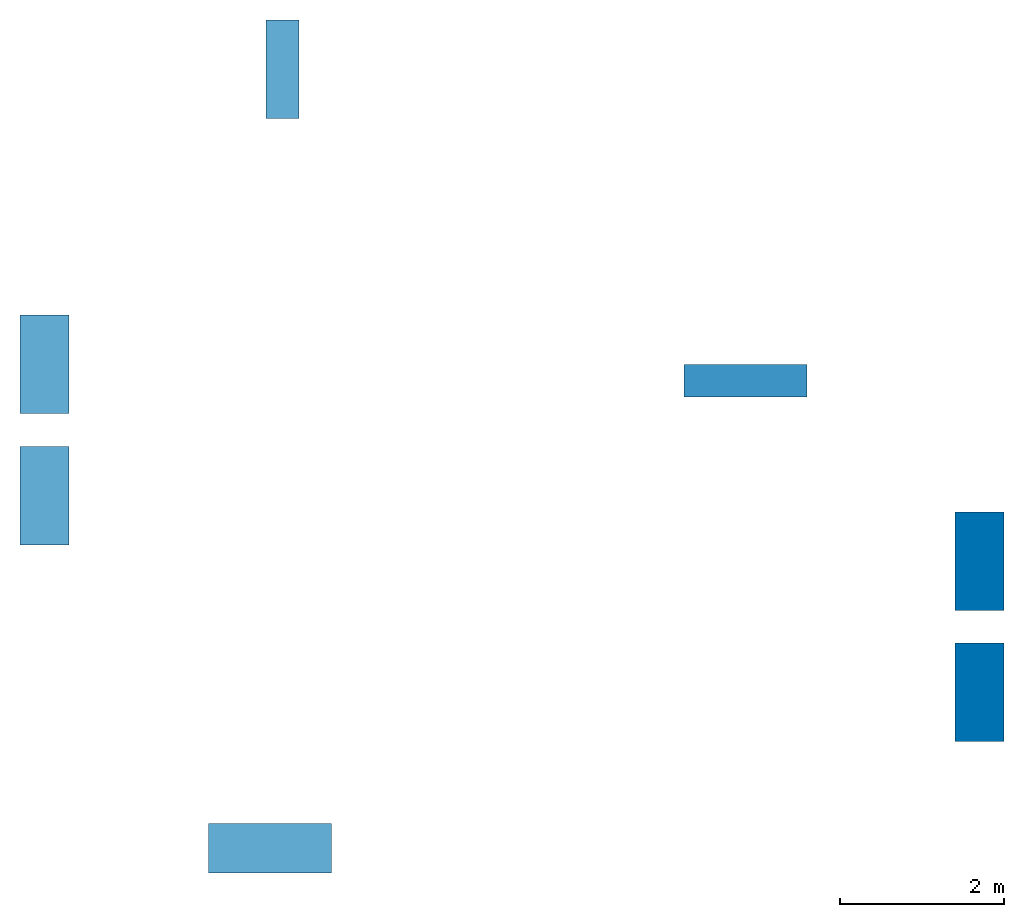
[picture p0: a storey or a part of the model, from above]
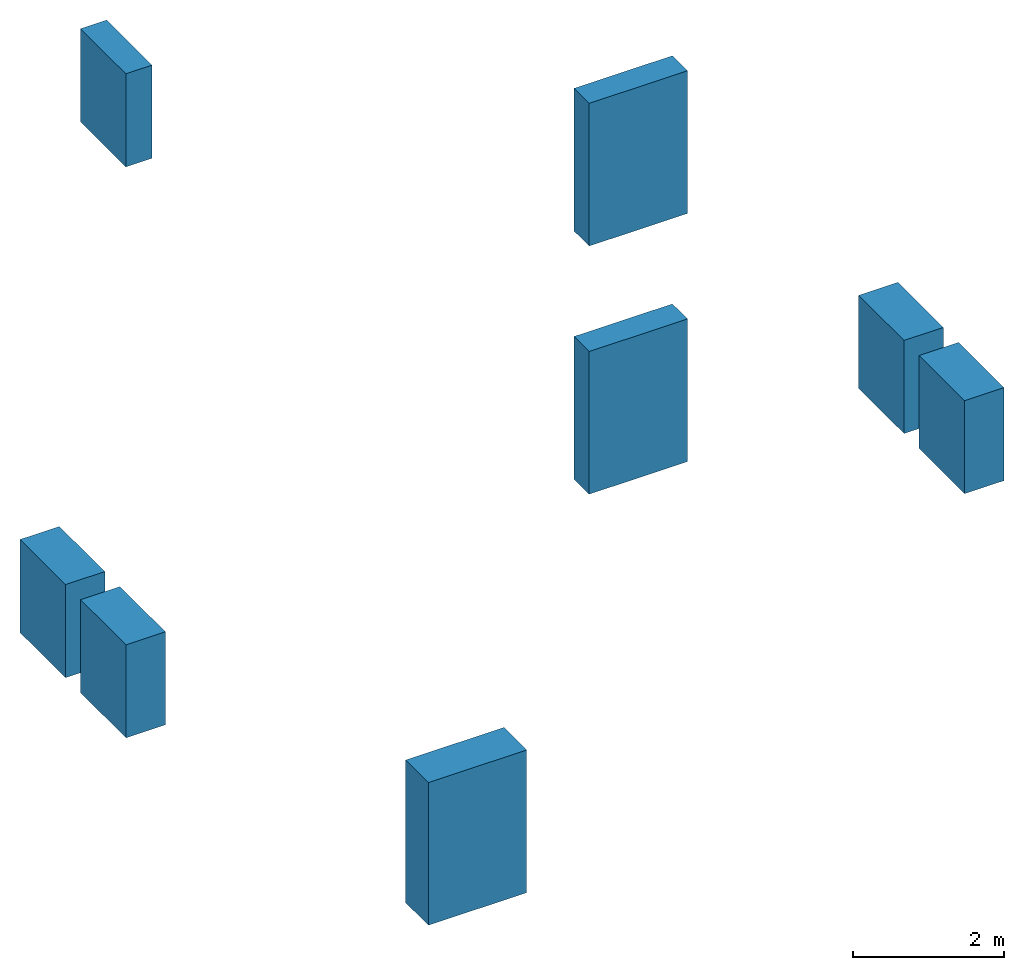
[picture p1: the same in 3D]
Properties of the parts of a building model (IFC2X3)

# File
Description: ViewDefinition[CoordinationView_V2.0, QuantityTakeOffAddOnView], Option [BaseQuantities:On], Option [GridExport:On], Option [Assemblies:On], Option [Bolts:On], Option [Rebars:On], Option [PourObjects:Off], Option [Welds:Off], Option [SurfaceTreatments:On], Option [LocationBy:0], Option [ViewColors:Off], Option [SectionedSpine:Off], Option [PropertySets:On], Option [Export all:Off]
File name: VTZ_geom_AR.ifc
Time: 2024-01-23T11:35:08
Author: VNIPIET\18962017
Organization: Structural Designer
Written by: IFC Database version: Work
Made in: Tekla Structures 2021 Service Pack 11, IFC Export Version: 4.0.0.0 Nov 13 2022

# IfcBuildingStorey, Undefined
In: Undefined
Elevation: 0 mm

# IfcElementAssembly (8)
In: Undefined
PredefinedType: REINFORCEMENT_UNIT
Name | Width (mm)
5 x Wall | 600
3 x Wall | 400

# IfcWall: 1500*400, Wall
In: Undefined
Description: 1500*400; Material: CONCRETE/Opening
BaseQuantities - Length: 1200 mm; OuterSurfaceArea: 5.76 m2; NetVolume: 0.72 m3; NetWeight: 0 kg; Width: 400 mm; GrossFootprintArea: 0.48 m2

# IfcWall: 1500*600 (4)
In: Undefined
Description: 1500*600; Material: CONCRETE/Opening
BaseQuantities - Length: 1200 mm; OuterSurfaceArea: 6.84 m2; NetVolume: 1.08 m3; NetWeight: 0 kg; Width: 600 mm; GrossFootprintArea: 0.72 m2

# IfcWall: 2300*400 (2)
In: Undefined
Description: 2300*400; Material: CONCRETE/Opening
BaseQuantities - Length: 1500 mm; OuterSurfaceArea: 9.94 m2; NetVolume: 1.38 m3; NetWeight: 0 kg; Width: 400 mm; GrossFootprintArea: 0.6 m2

# IfcWall: 2300*600, Wall
In: Undefined
Description: 2300*600; Material: CONCRETE/Opening
BaseQuantities - Length: 1500 mm; OuterSurfaceArea: 11.46 m2; NetVolume: 2.07 m3; NetWeight: 0 kg; Width: 600 mm; GrossFootprintArea: 0.9 m2
